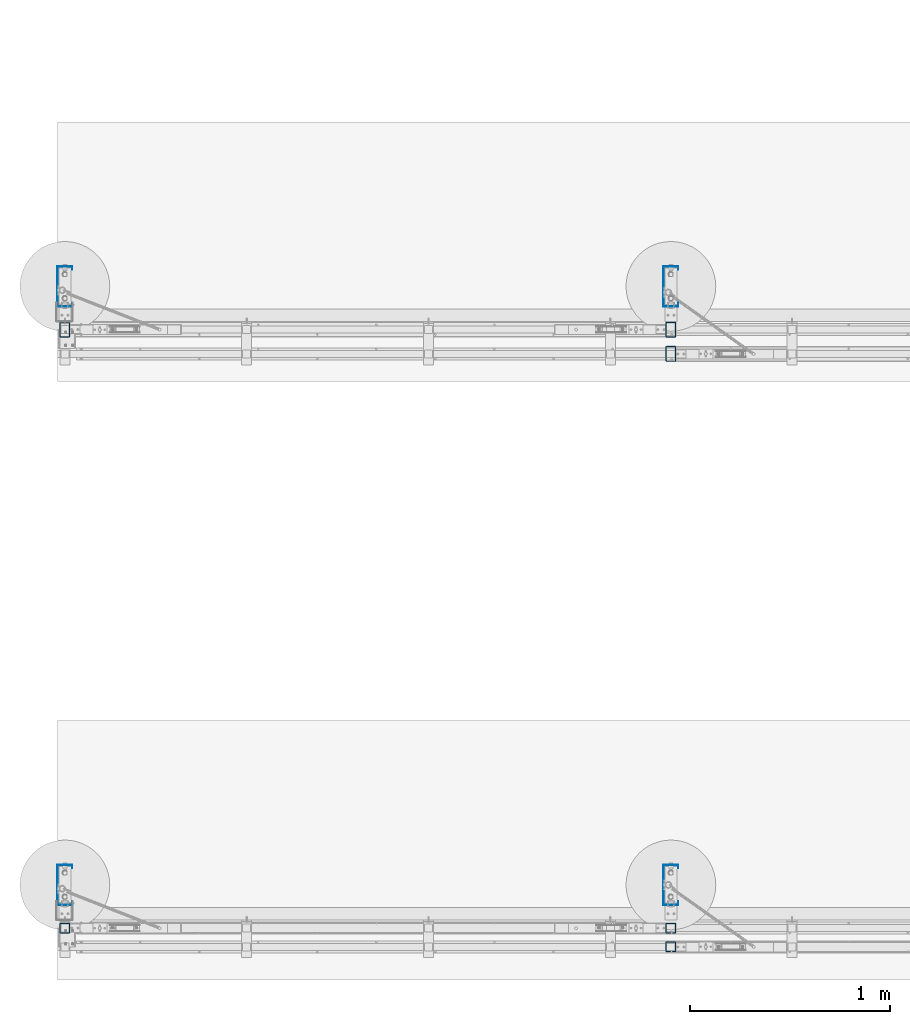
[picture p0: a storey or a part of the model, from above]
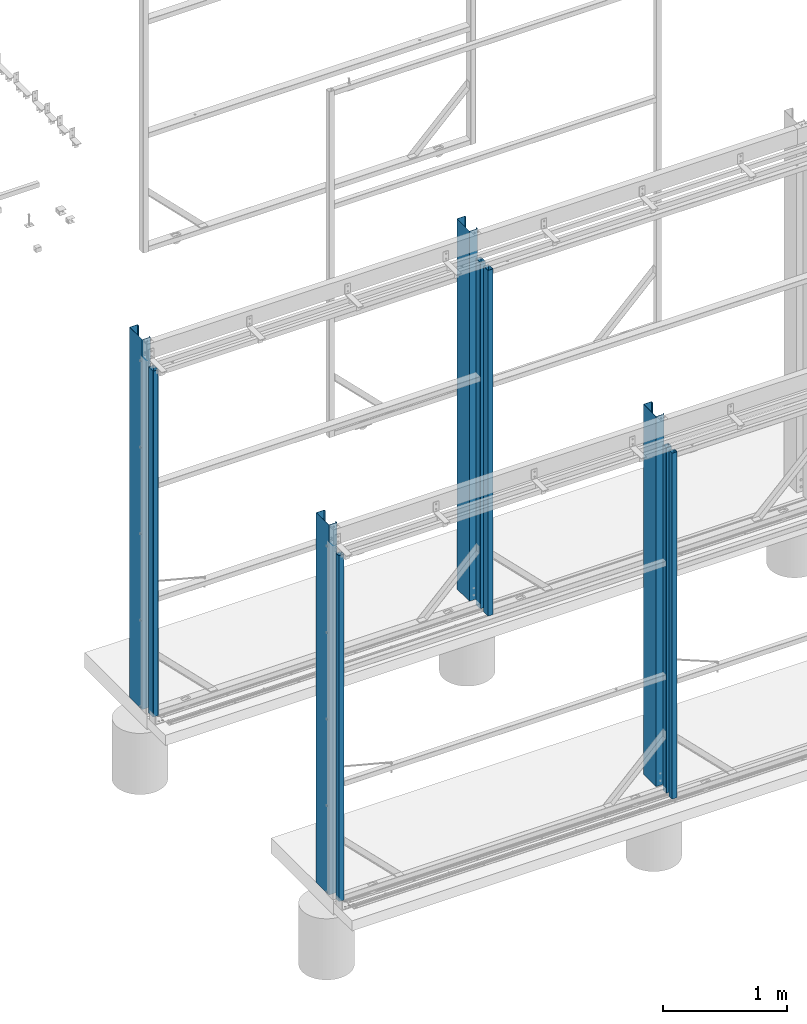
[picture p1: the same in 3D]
Properties of the parts of a building model (IFC2X3)

# File
Description: ViewDefinition[CoordinationView_V2.0, QuantityTakeOffAddOnView], Option [BaseQuantities:On], Option [GridExport:On], Option [Assemblies:On], Option [Bolts:On], Option [Rebars:On], Option [PourObjects:Off], Option [Welds:Off], Option [SurfaceTreatments:Off], Option [LocationBy:0], Option [ViewColors:Off], Option [SectionedSpine:Off], Option [PropertySets:On], Option [Export all:Off]
File name: Sliding Door.ifc
Time: 2026-09-21T11:43:24
Author: DESKTOP-BKNQL56\admin
Organization: Structural Designer
Written by: IFC Database Version: Work
Made in: Tekla Structures 2019 Service Pack 13, IFC Export Version: 4.0.0.0 Oct 18 2021

# IfcBuildingStorey, Undefined
In: Undefined
Elevation: 0 mm

# IfcBeam: C:150-19 (4)
In: Undefined
Description: C:150-19; Material: STEEL/G450
Tekla Common - Bottom elevation: +3.444; Top elevation: +3.596; Phase: 1; Class: 1
Tekla Quantity - Volume: 0 m3; Area per tons: 139.6 m2; Height: 152 mm; Width: 64 mm
Pset_BeamCommon - LoadBearing: no
Name | ASSEMBLY_POS = Reference | Weight (kg) | Gross footprint area (m2) | Net surface area (m2) | Tekla Quantity, Length (mm) = BaseQuantities, Length (mm) | OuterSurfaceArea (m2) | NetVolume (m3) | NetWeight (kg)
2 x FASCIA | Z/3676 | 13.9 | 0.2 | 1.9 | 3150.5 | 1.93746 | 0.00182811 | 14.3507
2 x FASCIA | Z/3652 | 26.6 | 0.3 | 3.7 | 6038 | 3.71212 | 0.00350361 | 27.5033

# IfcBeam: CC35-1.5-7-45 (5)
In: Undefined
Description: CC35-1.5-7-45
Tekla Common - Phase: 1; Class: 1
Tekla Quantity - Volume: 0 m3; Height: 35 mm; Width: 45 mm
Pset_BeamCommon - LoadBearing: no
Name | Material | ASSEMBLY_POS = Reference | Bottom elevation | Top elevation | Weight (kg) | Gross footprint area (m2) | Area per tons (m2) | Net surface area (m2) | Tekla Quantity, Length (mm) = BaseQuantities, Length (mm) | OuterSurfaceArea (m2) | NetVolume (m3) | NetWeight (kg)
TOP TRACK | STEEL/Steel_Undefined | TT/1 | +3.394 | +3.439 | 0.8 | 0 | 172.3 | 0.1 | 500 | 0.134899 | 0.00009975 | 0.783038
4 x TOP TRACK | STEEL/250 | Z/3674 | +3.397 | +3.442 | 14.4 | 0.3 | 171.8 | 2.5 | 9188.5 | 2.47211 | 0.00183311 | 14.3899

# IfcBeam: CC41-1.5-7-53, TOP TRACK BRACKET
In: Undefined
Description: CC41-1.5-7-53; Material: STEEL/Steel_Undefined
Default - ASSEMBLY_POS: SDB/9
Tekla Common - Bottom elevation: +3.388; Top elevation: +3.441; Phase: 1; Class: 1
Tekla Quantity - Weight: 0.1 kg; Volume: 0 m3; Gross footprint area: 0 m2; Area per tons: 177.9 m2; Net surface area: 0 m2; Height: 41 mm; Width: 53 mm; Length: 40 mm
Pset_BeamCommon - LoadBearing: no; Reference: SDB/9
BaseQuantities - Length: 40 mm; OuterSurfaceArea: 0.012985 m2; NetVolume: 0.0000093 m3; NetWeight: 0.073005 kg

# IfcBeam: CFCHS20*3 (4)
In: Undefined
Description: CFCHS20*3; Material: STEEL/250
Default - ASSEMBLY_POS: Z/3654
Tekla Common - Bottom elevation: -0.057; Top elevation: -0.044; Phase: 1; Class: 2
Tekla Quantity - Weight: 14.8 kg; Volume: 0 m3; Gross footprint area: 0 m2; Area per tons: 53.5 m2; Net surface area: 0.8 m2; Height: 60 mm; Width: 13 mm; Length: 8998.5 mm
Pset_BeamCommon - LoadBearing: no; Reference: Z/3654
BaseQuantities - Length: 8998.5 mm; OuterSurfaceArea: 0.794456 m2; NetVolume: 0.00189085 m3; NetWeight: 14.8432 kg

# IfcBeam: D12 (6)
In: Undefined
Description: D12; Material: STEEL/250
Default - ASSEMBLY_POS: Z/3662
Tekla Common - Bottom elevation: +1.062; Top elevation: +1.168; Phase: 1; Class: 5
Tekla Quantity - Weight: 0.5 kg; Volume: 0 m3; Gross footprint area: 0 m2; Area per tons: 46.4 m2; Net surface area: 0 m2; Height: 12 mm; Width: 12 mm; Length: 600 mm
Pset_BeamCommon - LoadBearing: no; Reference: Z/3662
BaseQuantities - Length: 600 mm; OuterSurfaceArea: 0.0222462 m2; NetVolume: 0.000061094 m3; NetWeight: 0.479588 kg

# IfcBeam: D450 (8)
In: Undefined
Description: D450; Material: Undefined/Undefined
Default - ASSEMBLY_POS: Z/3643
Tekla Common - Bottom elevation: -0.782; Top elevation: -0.182; Phase: 1; Class: 1
Tekla Quantity - Weight: 0 kg; Volume: 0.1 m3; Gross footprint area: 0.2 m2; Area per tons: 0 m2; Net surface area: 1.2 m2; Height: 450 mm; Width: 450 mm; Length: 600 mm
Pset_BeamCommon - LoadBearing: no; Reference: Z/3643
BaseQuantities - Length: 600 mm; OuterSurfaceArea: 1.16363 m2; NetVolume: 0.0949421 m3; NetWeight: 0 kg

# IfcBeam: D5 (12)
In: Undefined
Description: D5; Material: STEEL/250
Default - ASSEMBLY_POS: Z/3657
Tekla Common - Phase: 1; Class: 5
Tekla Quantity - Weight: 0 kg; Volume: 0 m3; Gross footprint area: 0 m2; Area per tons: 112.3 m2; Net surface area: 0 m2; Height: 5 mm; Width: 0 mm; Length: 71.6 mm
Pset_BeamCommon - LoadBearing: no; Reference: Z/3657
BaseQuantities - Length: 71.6493 mm; OuterSurfaceArea: 0.00139882 m2; NetVolume: 0.00000158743 m3; NetWeight: 0.0124613 kg
Name | Bottom elevation | Top elevation
6 x LINKS | +1.145 | +1.180
6 x LINKS | +1.160 | +1.165

# IfcBeam: EA50*50*3 (13)
In: Undefined
Description: EA50*50*3; Material: STEEL/300PLUS
Tekla Common - Bottom elevation: +0.033; Top elevation: +0.592; Phase: 1; Class: 11
Tekla Quantity - Weight: 1.8 kg; Volume: 0 m3; Gross footprint area: 0 m2; Area per tons: 86.4 m2; Net surface area: 0.2 m2; Height: 50 mm; Width: 50 mm; Length: 790 mm
Pset_BeamCommon - LoadBearing: no
BaseQuantities - Length: 790 mm; OuterSurfaceArea: 0.158 m2; NetVolume: 0.000227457 m3; NetWeight: 1.78554 kg
Name | ASSEMBLY_POS = Reference
ANGLE BRACE | AB/1
12 x Angle Brace | Z/3661

# IfcBeam: EA90*90*8 (5)
In: Undefined
Description: EA90*90*8; Material: STEEL/300PLUS
Tekla Common - Bottom elevation: -0.057; Top elevation: +0.033; Phase: 1; Class: 2
Tekla Quantity - Weight: 1 kg; Volume: 0 m3; Gross footprint area: 0 m2; Area per tons: 33 m2; Net surface area: 0 m2; Height: 90 mm; Width: 90 mm; Length: 95 mm
Pset_BeamCommon - LoadBearing: no
BaseQuantities - Length: 95 mm; OuterSurfaceArea: 0.03325 m2; NetVolume: 0.0001276 m3; NetWeight: 1.00166 kg
Name | ASSEMBLY_POS = Reference
DOOR STOPPER | DS/1
4 x DOOR STOPPER | Z/3640

# IfcBeam: FL6*50 (38)
In: Undefined
Description: FL6*50; Material: STEEL/250
Tekla Common - Phase: 1
Tekla Quantity - Volume: 0 m3; Gross footprint area: 0 m2; Net surface area: 0 m2; Height: 50 mm; Width: 6 mm
Pset_BeamCommon - LoadBearing: no
Name | ASSEMBLY_POS = Reference | Bottom elevation | Top elevation | Class | Weight (kg) | Area per tons (m2) | Tekla Quantity, Length (mm) | BaseQuantities, Length (mm) | OuterSurfaceArea (m2) | NetVolume (m3) | NetWeight (kg)
SLIDING DOOR BRACKET | PL/2518 | +3.441 | +3.541 | 10 | 0.8 | 48.3 | 357.1 | 357.137 | 0.0405756 | 0.00010695 | 0.839558
SLIDING DOOR BRACKET | PL/2517 | +3.441 | +3.541 | 10 | 0.8 | 48.4 | 328.1 | 328.137 | 0.0373276 | 0.00009825 | 0.771263
SLIDING DOOR BRACKET | PL/2516 | +3.441 | +3.541 | 10 | 0.8 | 48.4 | 327.1 | 327.137 | 0.0372156 | 0.00009795 | 0.768908
SLIDING DOOR BRACKET | PL/2515 | +3.441 | +3.541 | 10 | 0.8 | 48.4 | 308.1 | 308.137 | 0.0350876 | 0.00009225 | 0.724163
SLIDING DOOR BRACKET | PL/2514 | +3.441 | +3.541 | 10 | 0.6 | 48.7 | 238.1 | 238.137 | 0.0272476 | 0.00007125 | 0.559313
SLIDING DOOR BRACKET | PL/2513 | +3.441 | +3.541 | 10 | 0.5 | 48.8 | 218.1 | 218.137 | 0.0250076 | 0.00006525 | 0.512213
SLIDING DOOR BRACKET | PL/2512 | +3.441 | +3.541 | 10 | 0.5 | 48.9 | 209.1 | 209.137 | 0.0239996 | 0.00006255 | 0.491018
SLIDING DOOR BRACKET | PL/2511 | +3.441 | +3.541 | 10 | 0.5 | 48.9 | 199.1 | 199.137 | 0.0228796 | 0.00005955 | 0.467468
SLIDING DOOR BRACKET | PL/2114 | +3.441 | +3.541 | 9 | 0.6 | 48.4 | 307.1 | 307.137 | 0.0349756 | 0.00009195 | 0.721808
SLIDING DOOR BRACKET | PL/2107 | +3.441 | +3.541 | 9 | 0.6 | 48.6 | 277.1 | 277.137 | 0.0316156 | 0.00008295 | 0.651158
SLIDING DOOR BRACKET | PL/2090 | +3.441 | +3.541 | 9 | 0.6 | 48.6 | 258.1 | 258.137 | 0.0294876 | 0.00007725 | 0.606413
SLIDING DOOR BRACKET | PL/2089 | +3.441 | +3.541 | 9 | 0.6 | 48.4 | 278.1 | 278.137 | 0.0317276 | 0.00008325 | 0.653513
SLIDING DOOR BRACKET | PL/2071 | +3.441 | +3.541 | 9 | 0.5 | 48.9 | 213.1 | 213.137 | 0.0244476 | 0.00006375 | 0.500438
SLIDING DOOR BRACKET | PL/2070 | +3.441 | +3.541 | 9 | 0.5 | 48.9 | 193.1 | 193.137 | 0.0222076 | 0.00005775 | 0.453338
SLIDING DOOR BRACKET | PL/2049 | +3.441 | +3.541 | 9 | 0.5 | 49.1 | 184.1 | 184.137 | 0.0211996 | 0.00005505 | 0.432143
SLIDING DOOR BRACKET | PL/2048 | +3.441 | +3.541 | 9 | 0.5 | 49.1 | 174.1 | 174.137 | 0.0200796 | 0.00005205 | 0.408593
11 x DOOR BRACKET | Z/3659 | +3.444 | +3.544 | 10 | 0.6 | 48.4 | 308.1 | 308.137 | 0.0350876 | 0.00009225 | 0.724163
11 x DOOR BRACKET | Z/3647 | +3.444 | +3.544 | 9 | 0.6 | 48.4 | 278.1 | 278.137 | 0.0317276 | 0.00008325 | 0.653513

# IfcBeam: PLT1*263.6 (4)
In: Undefined
Description: PLT1*263.6; Material: STEEL/250
Default - ASSEMBLY_POS: Z/3641
Tekla Common - Bottom elevation: -0.032; Top elevation: +3.438; Phase: 1; Class: 1
Tekla Quantity - Weight: 7.2 kg; Volume: 0 m3; Gross footprint area: 0 m2; Area per tons: 256.3 m2; Net surface area: 1.8 m2; Height: 263.6 mm; Width: 1 mm; Length: 3470 mm
Pset_BeamCommon - LoadBearing: no; Reference: Z/3641
BaseQuantities - Length: 3470 mm; OuterSurfaceArea: 1.8464 m2; NetVolume: 0.000917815 m3; NetWeight: 7.20485 kg

# IfcBeam: PLT1.6*60 (8)
In: Undefined
Description: PLT1.6*60; Material: STEEL/250
Tekla Common - Bottom elevation: +3.441; Top elevation: +3.599; Phase: 1; Class: 1
Tekla Quantity - Weight: 0.2 kg; Volume: 0 m3; Gross footprint area: 0 m2; Area per tons: 164.6 m2; Net surface area: 0 m2; Height: 60 mm; Width: 1.6 mm; Length: 297.9 mm
Pset_BeamCommon - LoadBearing: no
BaseQuantities - Length: 297.881 mm; OuterSurfaceArea: 0.0371807 m2; NetVolume: 0.0000287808 m3; NetWeight: 0.225929 kg
Name | ASSEMBLY_POS = Reference
6 x FASCIA BRACKET | Z/52
2 x FASCIA BRACKET | Z/3655

# IfcBeam: PLT3*44, PLATE
In: Undefined
Description: PLT3*44; Material: STEEL/450
Tekla Quantity - Weight: 0.2 kg; Volume: 0 m3; Gross footprint area: 0 m2; Area per tons: 92.7 m2; Net surface area: 0 m2; Height: 44 mm; Width: 3 mm; Length: 156.8 mm
Tekla Common - Bottom elevation: +3.329; Top elevation: +3.373; Phase: 1; Class: 2
Default - ASSEMBLY_POS: PL/2519
Pset_BeamCommon - LoadBearing: no; Reference: PL/2519
BaseQuantities - Length: 156.85 mm; OuterSurfaceArea: 0.0154208 m2; NetVolume: 0.000021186 m3; NetWeight: 0.16631 kg

# IfcBeam: PLT3*65, PLATE
In: Undefined
Description: PLT3*65; Material: STEEL/450
Tekla Quantity - Weight: 0.2 kg; Volume: 0 m3; Gross footprint area: 0 m2; Area per tons: 90.9 m2; Net surface area: 0 m2; Height: 65 mm; Width: 3 mm; Length: 156.8 mm
Default - ASSEMBLY_POS: PL/2520
Tekla Common - Bottom elevation: +3.328; Top elevation: +3.372; Phase: 1; Class: 2
Pset_BeamCommon - LoadBearing: no; Reference: PL/2520
BaseQuantities - Length: 156.85 mm; OuterSurfaceArea: 0.0223212 m2; NetVolume: 0.0000312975 m3; NetWeight: 0.245685 kg

# IfcBeam: PLT6*61 (8)
In: Undefined
Description: PLT6*61; Material: STEEL/450
Default - ASSEMBLY_POS: Z/529
Tekla Common - Finish: GALVANIZE; Bottom elevation: -0.032; Top elevation: +0.123; Phase: 1; Class: 1
Tekla Quantity - Weight: 1.4 kg; Volume: 0 m3; Gross footprint area: 0 m2; Area per tons: 47.2 m2; Net surface area: 0.1 m2; Height: 61 mm; Width: 6 mm; Length: 481.9 mm
Pset_BeamCommon - LoadBearing: no; Reference: Z/529
BaseQuantities - Length: 481.908 mm; OuterSurfaceArea: 0.0665221 m2; NetVolume: 0.000179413 m3; NetWeight: 1.40839 kg

# IfcBeam: RHS:75x50x2.0 (13)
In: Undefined
Description: RHS:75x50x2.0
Tekla Quantity - Weight: 11.1 kg; Volume: 0 m3; Gross footprint area: 0.2 m2; Area per tons: 65.3 m2; Height: 75 mm; Width: 50 mm; Length: 2987.5 mm
Tekla Common - Phase: 1; Class: 14
Pset_BeamCommon - LoadBearing: no
BaseQuantities - Length: 2987.5 mm; OuterSurfaceArea: 0.725962 m2
Name | Material | Net surface area (m2) | ASSEMBLY_POS = Reference | Bottom elevation | Top elevation | NetVolume (m3) | NetWeight (kg)
Sliding Door Beam | STEEL/300PLUS | 0.8 | SDB/8 | +3.326 | +3.376 | 0.00144595 | 11.3507
3 x SLIDING DOOR | STEEL/300 | 0.6 | Z/3668 | +2.212 | +2.262 | 0.00144595 | 11.3507
SLIDING DOOR | STEEL/300 | 0.6 | Z/3678 | +1.097 | +1.147 | 0.00144595 | 11.3507
3 x SLIDING DOOR | STEEL/300 | 0.6 | Z/3666 | -0.017 | +0.033 | 0.00141859 | 11.1359
3 x SLIDING DOOR | STEEL/300 | 0.6 | Z/3669 | +3.326 | +3.376 | 0.00144595 | 11.3507
SLIDING DOOR | STEEL/300 | 0.6 | Z/3675 | +1.097 | +1.147 | 0.00144595 | 11.3507
SLIDING DOOR | STEEL/300 | 0.6 | Z/3667 | +1.097 | +1.147 | 0.00144595 | 11.3507

# IfcBeam: SHS:45X45X1.6, SLIDING DOOR INSERT
In: Undefined
Description: SHS:45X45X1.6; Material: STEEL/300PLUS
Default - ASSEMBLY_POS: Z/0(?)
Tekla Common - Bottom elevation: +3.329; Top elevation: +3.373; Phase: 1; Class: 1
Tekla Quantity - Weight: 0.1 kg; Volume: 0 m3; Gross footprint area: 0 m2; Area per tons: 82 m2; Net surface area: 0 m2; Height: 45 mm; Width: 45 mm; Length: 50 mm
Pset_BeamCommon - LoadBearing: no; Reference: Z/0(?)
BaseQuantities - Length: 50 mm; OuterSurfaceArea: 0.00975 m2; NetVolume: 0.000013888 m3; NetWeight: 0.109021 kg

# IfcBeam: SHS:50x50x2.0 (13)
In: Undefined
Description: SHS:50x50x2.0
Tekla Quantity - Weight: 8.8 kg; Volume: 0 m3; Gross footprint area: 0.1 m2; Area per tons: 65.7 m2; Net surface area: 0.6 m2; Height: 50 mm; Width: 50 mm; Length: 2987.5 mm
Tekla Common - Phase: 1; Class: 8
Pset_BeamCommon - LoadBearing: no
BaseQuantities - Length: 2987.5 mm; OuterSurfaceArea: 0.576588 m2
Name | Material | ASSEMBLY_POS = Reference | Bottom elevation | Top elevation | NetVolume (m3) | NetWeight (kg)
Sliding Door Beam | STEEL/300PLUS | SDB/4 | +3.326 | +3.376 | 0.0011472 | 9.00552
3 x SLIDING DOOR | STEEL/300 | Z/3665 | +2.212 | +2.262 | 0.0011472 | 9.00552
SLIDING DOOR | STEEL/300 | Z/3677 | +1.097 | +1.147 | 0.0011472 | 9.00552
3 x SLIDING DOOR | STEEL/300 | Z/3649 | -0.017 | +0.033 | 0.00111984 | 8.79074
3 x SLIDING DOOR | STEEL/300 | Z/3650 | +3.326 | +3.376 | 0.0011472 | 9.00552
SLIDING DOOR | STEEL/300 | Z/3673 | +1.097 | +1.147 | 0.0011472 | 9.00552
SLIDING DOOR | STEEL/300 | Z/3664 | +1.097 | +1.147 | 0.0011472 | 9.00552

# IfcColumn: C:200-19 (8)
In: Undefined
Description: C:200-19; Material: STEEL/G450
Default - ASSEMBLY_POS: Z/3644
Tekla Common - Bottom elevation: -0.032; Top elevation: +3.600; Phase: 1; Class: 1
Tekla Quantity - Weight: 20.3 kg; Volume: 0 m3; Gross footprint area: 0 m2; Area per tons: 138.5 m2; Net surface area: 2.8 m2; Height: 203 mm; Width: 76 mm; Length: 3632 mm
Pset_ColumnCommon - LoadBearing: no; Reference: Z/3644
BaseQuantities - Length: 3632 mm; OuterSurfaceArea: 2.81481 m2; NetVolume: 0.00265957 m3; NetWeight: 20.8776 kg

# IfcColumn: D12 (12)
In: Undefined
Description: D12; Material: STEEL/250
Tekla Common - Bottom elevation: +3.320; Top elevation: +3.430; Phase: 1; Class: 11
Tekla Quantity - Weight: 0.1 kg; Volume: 0 m3; Gross footprint area: 0 m2; Area per tons: 51.7 m2; Net surface area: 0 m2; Height: 12 mm; Width: 12 mm; Length: 110 mm
Pset_ColumnCommon - LoadBearing: no
BaseQuantities - Length: 110 mm; OuterSurfaceArea: 0.00438944 m2; NetVolume: 0.0000108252 m3; NetWeight: 0.0849779 kg
Name | ASSEMBLY_POS = Reference
6 x ROD | Z/3660
6 x ROD | Z/3645

# IfcColumn: D16 (16)
In: Undefined
Description: D16; Material: STEEL/300
Default - ASSEMBLY_POS: Z/65
Tekla Common - Bottom elevation: -0.151; Top elevation: -0.001; Phase: 1; Class: 1
Tekla Quantity - Weight: 0.2 kg; Volume: 0 m3; Gross footprint area: 0 m2; Area per tons: 36.2 m2; Net surface area: 0 m2; Height: 16 mm; Width: 16 mm; Length: 150 mm
Pset_ColumnCommon - LoadBearing: no; Reference: Z/65
BaseQuantities - Length: 150 mm; OuterSurfaceArea: 0.00770956 m2; NetVolume: 0.0000271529 m3; NetWeight: 0.21315 kg

# IfcColumn: RHS:75x50x2.0 (6)
In: Undefined
Description: RHS:75x50x2.0; Material: STEEL/300
Tekla Common - Bottom elevation: -0.017; Top elevation: +3.376; Phase: 1; Class: 14
Tekla Quantity - Weight: 12.6 kg; Volume: 0 m3; Gross footprint area: 0 m2; Area per tons: 65.3 m2; Net surface area: 0.8 m2; Height: 75 mm; Width: 50 mm; Length: 3393 mm
Default - ASSEMBLY_POS: Z/3658
Pset_ColumnCommon - LoadBearing: no; Reference: Z/3658
BaseQuantities - Length: 3393 mm; OuterSurfaceArea: 0.824499 m2; NetVolume: 0.00164221 m3; NetWeight: 12.8914 kg

# IfcColumn: SHS:50x50x2.0 (6)
In: Undefined
Description: SHS:50x50x2.0; Material: STEEL/300
Tekla Common - Bottom elevation: -0.017; Top elevation: +3.376; Phase: 1; Class: 8
Tekla Quantity - Weight: 10 kg; Volume: 0 m3; Gross footprint area: 0 m2; Area per tons: 65.7 m2; Net surface area: 0.6 m2; Height: 50 mm; Width: 50 mm; Length: 3393 mm
Pset_ColumnCommon - LoadBearing: no
BaseQuantities - Length: 3393 mm; OuterSurfaceArea: 0.654849 m2; NetVolume: 0.00130291 m3; NetWeight: 10.2279 kg
Name | ASSEMBLY_POS = Reference
4 x SLIDING DOOR | Z/3670
SLIDING DOOR | Z/3671
SLIDING DOOR | Z/3642

# IfcDiscreteAccessory: Angle Brace (4)
In: Undefined
Description: EA50*50*3; Material: STEEL/300PLUS
Tekla Common - Bottom elevation: +0.033; Top elevation: +0.592; Phase: 1; Class: 11
Tekla Quantity - Weight: 1.8 kg; Volume: 0 m3; Gross footprint area: 0 m2; Area per tons: 86.4 m2; Net surface area: 0.2 m2; Height: 50 mm; Width: 50 mm; Length: 790 mm
Pset_PlateCommon - LoadBearing: no; Reference: z/2810
BaseQuantities - NetArea: 0.158 m2; GrossArea: 0.158 m2; CrossSectionArea: 0.000295 m2; NetVolume: 0.000227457 m3; GrossVolume: 0.00023305 m3

# IfcDiscreteAccessory: DB-BU90 (4)
In: Undefined
Description: D88; Material: STEEL/250
Tekla Common - Bottom elevation: -0.054; Top elevation: +0.034; Phase: 1; Class: 5
Tekla Quantity - Weight: 1.2 kg; Volume: 0 m3; Gross footprint area: 0 m2; Area per tons: 16.1 m2; Net surface area: 0 m2; Height: 88 mm; Width: 88 mm; Length: 25 mm
Pset_PlateCommon - LoadBearing: no; Reference: z/2824
BaseQuantities - NetArea: 0.0187212 m2; GrossArea: 0.0187212 m2; CrossSectionArea: 0.005927 m2; NetVolume: 0.000148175 m3; GrossVolume: 0.000148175 m3

# IfcDiscreteAccessory: DOOR ROLLER (12)
In: Undefined
Description: D88; Material: STEEL/250
Tekla Common - Bottom elevation: -0.054; Top elevation: +0.034; Phase: 1; Class: 5
Tekla Quantity - Weight: 1.2 kg; Volume: 0 m3; Gross footprint area: 0 m2; Area per tons: 16.1 m2; Net surface area: 0 m2; Height: 88 mm; Width: 88 mm; Length: 25 mm
BaseQuantities - NetArea: 0.0187212 m2; GrossArea: 0.0187212 m2; CrossSectionArea: 0.005927 m2; NetVolume: 0.000148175 m3; GrossVolume: 0.000148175 m3
Pset_PlateCommon - LoadBearing: no; Reference: z/2791

# IfcDiscreteAccessory: LINK (2)
In: Undefined
Description: D5; Material: STEEL/250
Tekla Quantity - Weight: 0 kg; Volume: 0 m3; Gross footprint area: 0 m2; Area per tons: 112.3 m2; Net surface area: 0 m2; Height: 5 mm; Width: 0 mm; Length: 71.6 mm
Tekla Common - Phase: 1; Class: 5
Pset_PlateCommon - LoadBearing: no; Reference: z/2805
BaseQuantities - NetArea: 0.00139882 m2; GrossArea: 0.00163636 m2; CrossSectionArea: 0.0000176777 m2; NetVolume: 0.00000158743 m3; GrossVolume: 0.00000189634 m3
Name | Bottom elevation | Top elevation
LINK | -0.009 | -0.004
LINK | -0.019 | +0.007

# IfcDiscreteAccessory: PLATE (68)
In: Undefined
Tekla Common - Phase: 1
Tekla Quantity - Volume: 0 m3; Gross footprint area: 0 m2; Net surface area: 0 m2
Pset_PlateCommon - LoadBearing: no
Name | Description | Material | Bottom elevation | Top elevation | Class | Weight (kg) | Area per tons (m2) | Height (mm) | Width (mm) | Length (mm) | Reference | NetArea (m2) | GrossArea (m2) | CrossSectionArea (m2) | NetVolume (m3) | GrossVolume (m3)
2 x PLATE | PLT3*44 | STEEL/450 | -0.014 | +0.030 | 2 | 0.2 | 92.7 | 44 | 3 | 156.8 | z/2822 | 0.0154208 | 0.0154208 | 0.000132 | 0.000021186 | 0.000021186
2 x PLATE | PLT3*44 | STEEL/450 | +1.100 | +1.144 | 2 | 0.2 | 92.7 | 44 | 3 | 156.8 | z/2822 | 0.0154208 | 0.0154208 | 0.000132 | 0.000021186 | 0.000021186
2 x PLATE | PLT3*44 | STEEL/450 | +2.215 | +2.259 | 2 | 0.2 | 92.7 | 44 | 3 | 156.8 | z/2822 | 0.0154208 | 0.0154208 | 0.000132 | 0.000021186 | 0.000021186
2 x PLATE | PLT3*44 | STEEL/450 | +3.329 | +3.373 | 2 | 0.2 | 92.7 | 44 | 3 | 156.8 | z/2822 | 0.0154208 | 0.0154208 | 0.000132 | 0.000021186 | 0.000021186
2 x PLATE | PLT3*65 | STEEL/450 | -0.014 | +0.030 | 2 | 0.2 | 90.9 | 65 | 3 | 156.8 | z/2823 | 0.0223212 | 0.0223212 | 0.000195 | 0.0000312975 | 0.0000312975
2 x PLATE | PLT3*65 | STEEL/450 | +1.100 | +1.144 | 2 | 0.2 | 90.9 | 65 | 3 | 156.8 | z/2823 | 0.0223212 | 0.0223212 | 0.000195 | 0.0000312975 | 0.0000312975
2 x PLATE | PLT3*65 | STEEL/450 | +2.215 | +2.259 | 2 | 0.2 | 90.9 | 65 | 3 | 156.8 | z/2823 | 0.0223212 | 0.0223212 | 0.000195 | 0.0000312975 | 0.0000312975
2 x PLATE | PLT3*65 | STEEL/450 | +3.329 | +3.373 | 2 | 0.2 | 90.9 | 65 | 3 | 156.8 | z/2823 | 0.0223212 | 0.0223212 | 0.000195 | 0.0000312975 | 0.0000312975
32 x PLATE | PLT2*10 | STEEL/250 | -0.029 | -0.019 | 99 | 0 | 154.6 | 10 | 2 | 150 | z/2792 | 0.00364 | 0.0015 | 0.000004 | 0.000003 | 0.000003
4 x PLATE | PLT2*33 | STEEL/250 | -0.019 | -0.017 | 99 | 0 | 162.5 | 33 | 2 | 150 | z/2785 | 0.00574 | 0.00495 | 0.000004 | 0.0000045 | 0.0000099
8 x PLATE | PLT3*50 | STEEL/250 | +3.323 | +3.326 | 11 | 0.1 | 93.7 | 50 | 3 | 70 | p/1884 | 0.00772 | 0.0035 | 0.000009 | 0.0000105 | 0.0000105 | Tekla Common - Finish: GALVANIZE
8 x PLATE | PLT3*50 | STEEL/250 | +3.323 | +3.326 | 11 | 0.1 | 93.7 | 50 | 3 | 70 | z/2804 | 0.00772 | 0.0035 | 0.000009 | 0.0000105 | 0.0000105 | Tekla Common - Finish: GALVANIZE

# IfcDiscreteAccessory: ROD (6)
In: Undefined
Description: D12; Material: STEEL/250
Tekla Common - Phase: 1
Tekla Quantity - Volume: 0 m3; Gross footprint area: 0 m2; Net surface area: 0 m2; Height: 12 mm; Width: 12 mm
Pset_PlateCommon - LoadBearing: no
BaseQuantities - CrossSectionArea: 0.000101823 m2
Name | Bottom elevation | Top elevation | Class | Weight (kg) | Area per tons (m2) | Length (mm) | Reference | NetArea (m2) | GrossArea (m2) | NetVolume (m3) | GrossVolume (m3)
4 x ROD | +3.320 | +3.430 | 11 | 0.1 | 51.7 | 110 | z/2788 | 0.00438944 | 0.00424478 | 0.0000108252 | 0.0000112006
ROD | +3.320 | +3.430 | 11 | 0.1 | 51.7 | 110 | rd/2 | 0.00438944 | 0.00424478 | 0.0000108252 | 0.0000112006
ROD | -0.087 | -0.006 | 5 | 0.5 | 46.4 | 600 | rd/1 | 0.0222462 | 0.0222462 | 0.000061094 | 0.000061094

# IfcDiscreteAccessory: SLIDING DOOR (48)
In: Undefined
Description: SHS:45X45X1.6; Material: STEEL/300
Tekla Quantity - Weight: 0.1 kg; Volume: 0 m3; Gross footprint area: 0 m2; Area per tons: 82 m2; Net surface area: 0 m2; Height: 45 mm; Width: 45 mm; Length: 50 mm
Tekla Common - Phase: 1; Class: 11
Pset_PlateCommon - LoadBearing: no
BaseQuantities - NetArea: 0.00975 m2; GrossArea: 0.00975 m2; CrossSectionArea: 0.000303 m2; NetVolume: 0.000013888 m3; GrossVolume: 0.00001515 m3
Name | Bottom elevation | Top elevation | Reference
10 x SLIDING DOOR | +3.329 | +3.373 | z/2794
10 x SLIDING DOOR | +2.214 | +2.259 | z/2794
11 x SLIDING DOOR | +1.100 | +1.145 | z/2794
11 x SLIDING DOOR | -0.015 | +0.030 | z/2793
SLIDING DOOR | +3.329 | +3.373 | z/2800
SLIDING DOOR | +2.214 | +2.259 | z/2799
SLIDING DOOR | +1.100 | +1.145 | z/2798
SLIDING DOOR | -0.015 | +0.030 | z/2797
SLIDING DOOR | +3.329 | +3.373 | z/2796
SLIDING DOOR | +2.214 | +2.259 | z/2795

# IfcDiscreteAccessory: SLIDING DOOR BRACKET (44)
In: Undefined
Description: CC41-1.5-7-53; Material: STEEL/250
Tekla Quantity - Weight: 0.1 kg; Volume: 0 m3; Gross footprint area: 0 m2; Area per tons: 177.9 m2; Net surface area: 0 m2; Height: 41 mm; Width: 53 mm; Length: 40 mm
Tekla Common - Bottom elevation: +3.391; Top elevation: +3.444; Phase: 1; Class: 1
Pset_PlateCommon - LoadBearing: no; Reference: z/2790
BaseQuantities - NetArea: 0.012985 m2; GrossArea: 0.012985 m2; CrossSectionArea: 0.0002325 m2; NetVolume: 0.0000093 m3; GrossVolume: 0.0000093 m3

# IfcDiscreteAccessory: SPRING PIN (17)
In: Undefined
Description: D6; Material: STEEL/250
Tekla Common - Bottom elevation: +3.418; Top elevation: +3.424; Phase: 1; Class: 0
Tekla Quantity - Weight: 0 kg; Volume: 0 m3; Gross footprint area: 0 m2; Area per tons: 0 m2; Net surface area: 0 m2; Height: 6 mm; Width: 6 mm; Length: 30 mm
Pset_PlateCommon - LoadBearing: no
BaseQuantities - NetArea: 0.000601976 m2; GrossArea: 0.000601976 m2; CrossSectionArea: 0.0000254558 m2; NetVolume: 7.63675e-07 m3; GrossVolume: 7.63675e-07 m3
Name | Reference
16 x SPRING PIN | z/2801
SPRING PIN | sp/1

# IfcDiscreteAccessory: Sliding Door Beam (6)
In: Undefined
Material: STEEL/300PLUS
Tekla Common - Phase: 1
Tekla Quantity - Volume: 0 m3; Width: 50 mm; Length: 2987.5 mm
Pset_PlateCommon - LoadBearing: no
Name | Description | Bottom elevation | Top elevation | Class | Weight (kg) | Gross footprint area (m2) | Area per tons (m2) | Net surface area (m2) | Height (mm) | Reference | NetArea (m2) = GrossArea (m2) | CrossSectionArea (m2) | NetVolume (m3) | GrossVolume (m3)
Sliding Door Beam | RHS:75x50x2.0 | +2.212 | +2.262 | 14 | 11.1 | 0.2 | 65.3 | 0.8 | 75 | sdb/9 | 0.725962 | 0.000474 | 0.00144595 | 0.00141607
Sliding Door Beam | RHS:75x50x2.0 | +1.097 | +1.147 | 14 | 11.1 | 0.2 | 65.3 | 0.8 | 75 | sdb/8 | 0.725962 | 0.000474 | 0.00144595 | 0.00141607
Sliding Door Beam | RHS:75x50x2.0 | -0.017 | +0.033 | 14 | 11.1 | 0.2 | 65.3 | 0.8 | 75 | sdb/7 | 0.725962 | 0.000474 | 0.00141859 | 0.00141607
Sliding Door Beam | SHS:50x50x2.0 | +2.212 | +2.262 | 8 | 8.8 | 0.1 | 65.7 | 0.6 | 50 | sdb/5 | 0.576588 | 0.000374 | 0.0011472 | 0.00111732
Sliding Door Beam | SHS:50x50x2.0 | +1.097 | +1.147 | 8 | 8.8 | 0.1 | 65.7 | 0.6 | 50 | sdb/4 | 0.576588 | 0.000374 | 0.0011472 | 0.00111732
Sliding Door Beam | SHS:50x50x2.0 | -0.017 | +0.033 | 8 | 8.8 | 0.1 | 65.7 | 0.6 | 50 | sdb/3 | 0.576588 | 0.000374 | 0.00111984 | 0.00111732

# IfcDiscreteAccessory: Sliding Door Post (4)
In: Undefined
Material: STEEL/300
Tekla Common - Bottom elevation: -0.017; Top elevation: +3.376; Phase: 1
Tekla Quantity - Volume: 0 m3; Gross footprint area: 0 m2; Net surface area: 0.8 m2; Width: 50 mm; Length: 3393 mm
Pset_PlateCommon - LoadBearing: no
Name | Description | Class | Weight (kg) | Area per tons (m2) | Height (mm) | Reference | NetArea (m2) = GrossArea (m2) | CrossSectionArea (m2) | NetVolume (m3) | GrossVolume (m3)
2 x Sliding Door Post | RHS:75x50x2.0 | 14 | 12.6 | 65.3 | 75 | sdp/2 | 0.824499 | 0.000474 | 0.00164221 | 0.00160828
2 x Sliding Door Post | SHS:50x50x2.0 | 8 | 10 | 65.7 | 50 | sdp/1 | 0.654849 | 0.000374 | 0.00130291 | 0.00126898

# IfcDiscreteAccessory: TOP TRACK BRACKET (24)
In: Undefined
Description: CC38-1.5-7-50; Material: STEEL/Steel_Undefined
Tekla Common - Bottom elevation: +3.391; Top elevation: +3.441; Phase: 1; Class: 1
Tekla Quantity - Weight: 0.1 kg; Volume: 0 m3; Gross footprint area: 0 m2; Area per tons: 177.9 m2; Net surface area: 0 m2; Height: 38 mm; Width: 50 mm; Length: 40 mm
Pset_PlateCommon - LoadBearing: no; Reference: z/2821
BaseQuantities - NetArea: 0.012238 m2; GrossArea: 0.012238 m2; CrossSectionArea: 0.000219 m2; NetVolume: 0.00000876 m3; GrossVolume: 0.00000876 m3

# IfcElementAssembly (217)
In: Undefined
Name | PredefinedType | ASSEMBLY_POS = Assembly/Cast unit Mark | Assembly/Cast unit weight (kg) | Assembly/Cast unit bottom elevation | Assembly/Cast unit top elevation | Width (mm)
Sliding Door Beam | RIGID_FRAME | SDB/4 | 62.8 | -0.054 | +3.430 | 3484
Sliding Door Beam | RIGID_FRAME | SDB/8 | 78.2 | -0.054 | +3.430 | 3484
PLATE | RIGID_FRAME | PL/2519 | 0.2 | +3.329 | +3.373 | 44
PLATE | RIGID_FRAME | PL/2520 | 0.2 | +3.328 | +3.372 | 44
DOOR STOPPER | RIGID_FRAME | DS/1 | 1 | -0.057 | +0.033 | 90
TOP TRACK BRACKET | RIGID_FRAME | SDB/9 | 0.1 | +3.388 | +3.441 | 53
SLIDING DOOR INSERT | RIGID_FRAME | Z/0(?) | 0.1 | +3.329 | +3.373 | 45
PLATE | RIGID_FRAME | PL/2159 | 0.2 | +3.320 | +3.430 | 110
TOP TRACK | RIGID_FRAME | TT/1 | 0.8 | +3.394 | +3.439 | 45
ANGLE BRACE | RIGID_FRAME | AB/1 | 1.8 | +0.033 | +0.592 | 50
SLIDING DOOR BRACKET | RIGID_FRAME | PL/2518 | 1 | +3.391 | +3.541 | 267
SLIDING DOOR BRACKET | RIGID_FRAME | PL/2517 | 0.8 | +3.391 | +3.541 | 238
SLIDING DOOR BRACKET | RIGID_FRAME | PL/2516 | 0.8 | +3.391 | +3.541 | 237
SLIDING DOOR BRACKET | RIGID_FRAME | PL/2515 | 0.8 | +3.391 | +3.541 | 218
SLIDING DOOR BRACKET | RIGID_FRAME | PL/2514 | 0.6 | +3.391 | +3.541 | 148
SLIDING DOOR BRACKET | RIGID_FRAME | PL/2513 | 0.6 | +3.391 | +3.541 | 128
SLIDING DOOR BRACKET | RIGID_FRAME | PL/2512 | 0.6 | +3.391 | +3.541 | 119
SLIDING DOOR BRACKET | RIGID_FRAME | PL/2511 | 0.5 | +3.391 | +3.541 | 109
SLIDING DOOR BRACKET | RIGID_FRAME | PL/2114 | 0.8 | +3.391 | +3.541 | 217
SLIDING DOOR BRACKET | RIGID_FRAME | PL/2107 | 0.8 | +3.391 | +3.541 | 187
SLIDING DOOR BRACKET | RIGID_FRAME | PL/2090 | 0.6 | +3.391 | +3.541 | 168
SLIDING DOOR BRACKET | RIGID_FRAME | PL/2089 | 0.8 | +3.391 | +3.541 | 188
SLIDING DOOR BRACKET | RIGID_FRAME | PL/2071 | 0.6 | +3.391 | +3.541 | 123
SLIDING DOOR BRACKET | RIGID_FRAME | PL/2070 | 0.5 | +3.391 | +3.541 | 103
SLIDING DOOR BRACKET | RIGID_FRAME | PL/2049 | 0.5 | +3.391 | +3.541 | 94
SLIDING DOOR BRACKET | RIGID_FRAME | PL/2048 | 0.5 | +3.391 | +3.541 | 84
11 x DOOR BRACKET | RIGID_FRAME | Z/3659 | 0.8 | +3.391 | +3.544 | 218
6 x PLATE | RIGID_FRAME | Z/3651 | 0.2 | +1.112 | +1.212 | 6
SLIDING DOOR | RIGID_FRAME | Z/3678 | 11.1 | +1.097 | +1.147 | 50
SLIDING DOOR | RIGID_FRAME | Z/3675 | 11.1 | +1.097 | +1.147 | 50
SLIDING DOOR | RIGID_FRAME | Z/3667 | 11.1 | +1.097 | +1.147 | 50
4 x FOLDED CHANNEL | RIGID_FRAME | Z/3641 | 7.2 | -0.032 | +3.438 | 83
6 x ROD | RIGID_FRAME | Z/3660 | 0.2 | +3.320 | +3.430 | 50
12 x PLATE | RIGID_FRAME | Z/3648 | 1.2 | -0.054 | +0.034 | 88
6 x SLIDING DOOR | RIGID_FRAME | Z/3658 | 13.1 | -0.017 | +3.376 | 100
3 x SLIDING DOOR | RIGID_FRAME | Z/3669 | 11.1 | +3.326 | +3.376 | 50
4 x DOOR STOPPER | RIGID_FRAME | Z/3640 | 1 | -0.057 | +0.033 | 90
8 x BASEPLATE | RIGID_FRAME | Z/529 | 1.4 | -0.032 | +0.123 | 200.2
8 x COLUMN | RIGID_FRAME | Z/3644 | 20.3 | -0.032 | +3.600 | 76
4 x DOOR TRACK | RIGID_FRAME | Z/3654 | 14.8 | -0.057 | -0.044 | 13
6 x FASCIA BRACKET | RIGID_FRAME | Z/52 | 0.2 | +3.441 | +3.599 | 157.2
2 x FASCIA BRACKET | RIGID_FRAME | Z/3655 | 0.2 | +3.441 | +3.599 | 157.2
6 x LINKS | RIGID_FRAME | Z/3657 | 0 | +1.145 | +1.180 | 5
4 x ROD | RIGID_FRAME | Z/3662 | 0.5 | +1.062 | +1.168 | 12
6 x LINKS | RIGID_FRAME | Z/3657 | 0 | +1.160 | +1.165 | 5
2 x ROD | RIGID_FRAME | Z/3662 | 0.5 | +1.062 | +1.168 | 12.0001
12 x Angle Brace | RIGID_FRAME | Z/3661 | 1.8 | +0.033 | +0.592 | 50
3 x SLIDING DOOR | RIGID_FRAME | Z/3668 | 11.1 | +2.212 | +2.262 | 50
3 x SLIDING DOOR | RIGID_FRAME | Z/3666 | 11.1 | -0.017 | +0.033 | 50
4 x TOP TRACK | RIGID_FRAME | Z/3674 | 14.4 | +3.397 | +3.442 | 45
2 x SLAB | REINFORCEMENT_UNIT | Z/3656 | 3307.9 | -0.182 | -0.032 | 150 | Tekla Assembly - Cast unit type: Cast in place; Cast unit rebar weight: 0 kg
16 x THROUGH BOLTS | RIGID_FRAME | Z/65 | 0.2 | -0.151 | -0.001 | 16
8 x FOOTING |  | Z/3643 | 0 | -0.782 | -0.182 | 450
2 x SLAB | REINFORCEMENT_UNIT | Z/3653 | 661.6 | -0.157 | -0.057 | 100 | Tekla Assembly - Cast unit type: Cast in place; Cast unit rebar weight: 0 kg
2 x FASCIA | RIGID_FRAME | Z/3676 | 13.9 | +3.444 | +3.596 | 64
2 x FASCIA | RIGID_FRAME | Z/3652 | 26.6 | +3.444 | +3.596 | 64
11 x DOOR BRACKET | RIGID_FRAME | Z/3647 | 0.8 | +3.391 | +3.544 | 188
SLIDING DOOR | RIGID_FRAME | Z/3677 | 8.8 | +1.097 | +1.147 | 50
SLIDING DOOR | RIGID_FRAME | Z/3673 | 8.8 | +1.097 | +1.147 | 50
SLIDING DOOR | RIGID_FRAME | Z/3664 | 8.8 | +1.097 | +1.147 | 50
6 x ROD | RIGID_FRAME | Z/3645 | 0.2 | +3.320 | +3.430 | 50
4 x SLIDING DOOR | RIGID_FRAME | Z/3670 | 10.4 | -0.017 | +3.376 | 100
3 x SLIDING DOOR | RIGID_FRAME | Z/3650 | 8.8 | +3.326 | +3.376 | 50
3 x SLIDING DOOR | RIGID_FRAME | Z/3665 | 8.8 | +2.212 | +2.262 | 50
3 x SLIDING DOOR | RIGID_FRAME | Z/3649 | 8.8 | -0.017 | +0.033 | 50
PLATE | RIGID_FRAME | PL/2160 | 0.6 | -0.087 | +0.044 | 556.801
SLIDING DOOR | RIGID_FRAME | Z/3671 | 10.4 | -0.017 | +3.376 | 100
SLIDING DOOR | RIGID_FRAME | Z/3642 | 10.4 | -0.017 | +3.376 | 100

# IfcMechanicalFastener: Bolt assembly (477)
In: Undefined
Tekla Bolt - Location: Site
Name | NominalDiameter (mm) | NominalLength (mm) | Material = Bolt standard | Washer count | Washer diameter (mm) | Washer type | Washer name | Nut count | Nut type | Nut name | Slotted hole y (mm) | Slotted hole x (mm) | Bolt hole diameter (mm) | Bolt count | Bolt size (mm) | Bolt length (mm) | Bolt Name
68 x Bolt assembly | 6 | 25 | TEK_11TPIM | 2 | 6 | UNDEF_WASH | UNDEFINED_WASHER14G | 2 | UNDEF_NUT | UNDEFINED_NUTM6 | 0 | 0 | 6 | 2 | 6 | 25 | TEKSCREW_M6*25
20 x Bolt assembly | 6 | 8 | TEK_11TPIM | 0 | 6 | UNDEF_WASH | UNDEFINED_WASHER14G | 0 | UNDEF_NUT | UNDEFINED_NUTM6 | 0 | 0 | 6 | 2 | 6 | 8 | TEKSCREW_M6*25
5 x Bolt assembly | 6 | 7.8 | TEK_11TPIM | 0 | 6 | UNDEF_WASH | UNDEFINED_WASHER14G | 0 | UNDEF_NUT | UNDEFINED_NUTM6 | 0 | 0 | 6 | 4 | 6 | 7.8 | TEKSCREW_M6*25
38 x Bolt assembly | 6 | 25 | TEK_11TPIM | 4 | 6 | UNDEF_WASH | UNDEFINED_WASHER14G | 2 | UNDEF_NUT | UNDEFINED_NUTM6 | 0 | 0 | 6 | 2 | 6 | 25 | TEKSCREW_M6*25
34 x Bolt assembly | 6 | 3 | 8.8S | 0 | 6 | HARD | WASHERM6-HARD | 0 | 8.8-HEX | NUTM6-8.8-HEX | 0 | 0 | 6 | 1 | 6 | 3 | BOLTM6*5
17 x Bolt assembly | 12 | 3 | 8.8S | 0 | 12 | HARD | WASHERM12-HARD | 0 | 8.8-HEX | NUTM12-8.8-HEX | 0 | 0 | 14 | 1 | 14 | 3 | BOLTM12*16
12 x Bolt assembly | 12 | 49.9967 | 8.8S | 0 | 12 | HARD | WASHERM12-HARD | 0 | 8.8-HEX | NUTM12-8.8-HEX | 0 | 0 | 14 | 1 | 14 | 50 | BOLTM12*50
32 x Bolt assembly | 6 | 25 | TEK_11TPIM | 1 | 6 | UNDEF_WASH | UNDEFINED_WASHER14G | 1 | UNDEF_NUT | UNDEFINED_NUTM6 | 0 | 0 | 6 | 1 | 6 | 25 | TEKSCREW_M6*25
16 x Bolt assembly | 10 | 50 | 8.8S | 0 | 10 | HARD | WASHERM10-HARD | 0 | 8.8-HEX | NUTM10-8.8-HEX | 0 | 0 | 16 | 1 | 16 | 50 | BOLTM10*50
Bolt assembly | 6 | 6.6 | TEK_11TPIM | 0 | 6 | UNDEF_WASH | UNDEFINED_WASHER14G | 0 | UNDEF_NUT | UNDEFINED_NUTM6 | 0 | 0 | 6 | 2 | 6 | 6.6 | TEKSCREW_M6*25
16 x Bolt assembly | 6 | 16 | TEK_11TPIM | 0 | 6 | UNDEF_WASH | UNDEFINED_WASHER14G | 0 | UNDEF_NUT | UNDEFINED_NUTM6 | 0 | 0 | 6 | 2 | 6 | 16 | TEKSCREW_M6*25
28 x Bolt assembly | 6 | 6 | 8.8S | 0 | 6 | HARD | WASHERM6-HARD | 0 | 8.8-HEX | NUTM6-8.8-HEX | 0 | 0 | 6 | 1 | 6 | 6 | BOLTM6*10
8 x Bolt assembly | 5 | 25 | TEK_16TPIM | 10 | 5 | UNDEF_WASH | UNDEFINED_WASHER10G | 5 | UNDEF_NUT | UNDEFINED_NUTM5 | 0 | 0 | 7 | 5 | 5 | 25 | TEKSCREW_M5*25
12 x Bolt assembly | 5 | 25 | TEK_16TPIM | 18 | 5 | UNDEF_WASH | UNDEFINED_WASHER10G | 2 | UNDEF_NUT | UNDEFINED_NUTM5 | 0 | 0 | 7 | 2 | 5 | 25 | TEKSCREW_M5*25
8 x Bolt assembly | 20 | 16 | 8.8S | 0 | 20 | HARD | WASHERM20-HARD | 0 | 8.8-HEX | NUTM20-8.8-HEX | 0 | 0 | 20 | 2 | 20 | 16 | BOLTM20*25
16 x Bolt assembly | 12 | 30 | 8.8S | 2 | 12 | HARD | WASHERM12-HARD | 2 | 8.8-HEX | NUTM12-8.8-HEX | 4 | 8 | 14 | 2 | 12 | 30 | BOLTM12*30
120 x Bolt assembly | 6.16 | 25 | TEK_10TPII | 1 | 6.2 | UNDEF_WASH | UNDEFINED_WASHER14G | 1 | UNDEF_NUT | UNDEFINED_NUTM6 | 0 | 0 | 8.2 | 1 | 6.2 | 25 | TEKSCREW_14G*25
4 x Bolt assembly | 6.16 | 25 | TEK_10TPII | 2 | 6.2 | UNDEF_WASH | UNDEFINED_WASHER14G | 2 | UNDEF_NUT | UNDEFINED_NUTM6 | 0 | 0 | 8.2 | 2 | 6.2 | 25 | TEKSCREW_14G*25
16 x Bolt assembly | 5 | 25 | TEK_16TPIM | 4 | 5 | UNDEF_WASH | UNDEFINED_WASHER10G | 2 | UNDEF_NUT | UNDEFINED_NUTM5 | 0 | 0 | 7 | 2 | 5 | 25 | TEKSCREW_M5*25
6 x Bolt assembly | 5 | 25 | TEK_16TPIM | 8 | 5 | UNDEF_WASH | UNDEFINED_WASHER10G | 4 | UNDEF_NUT | UNDEFINED_NUTM5 | 0 | 0 | 7 | 4 | 5 | 25 | TEKSCREW_M5*25

# IfcPlate: FL6*50 (7)
In: Undefined
Description: FL6*50; Material: STEEL/250
Tekla Common - Phase: 1; Class: 5
Tekla Quantity - Weight: 0.2 kg; Volume: 0 m3; Gross footprint area: 0 m2; Area per tons: 50.1 m2; Net surface area: 0 m2; Height: 50 mm; Width: 6 mm; Length: 100 mm
Pset_PlateCommon - LoadBearing: no
BaseQuantities - Width: 50 mm; NetArea: 0.0118 m2; GrossArea: 0.005 m2; CrossSectionArea: 0.000036 m2; NetVolume: 0.00003 m3; GrossVolume: 0.00003 m3
Name | ASSEMBLY_POS = Reference | Bottom elevation | Top elevation
6 x PLATE | Z/3651 | +1.112 | +1.212
PLATE | PL/2160 | -0.056 | +0.044

# IfcPlate: PLT2*33 (12)
In: Undefined
Description: PLT2*33; Material: STEEL/250
Tekla Common - Bottom elevation: -0.019; Top elevation: -0.017; Phase: 1; Class: 99
Tekla Quantity - Weight: 0 kg; Volume: 0 m3; Gross footprint area: 0 m2; Area per tons: 162.5 m2; Net surface area: 0 m2; Height: 33 mm; Width: 2 mm; Length: 150 mm
Default - ASSEMBLY_POS: Z/3648
Pset_PlateCommon - LoadBearing: no; Reference: Z/3648
BaseQuantities - Width: 33 mm; NetArea: 0.00574 m2; GrossArea: 0.00495 m2; CrossSectionArea: 0.000004 m2; NetVolume: 0.0000045 m3; GrossVolume: 0.0000099 m3

# IfcPlate: PLT3*50, PLATE
In: Undefined
Description: PLT3*50; Material: STEEL/250
Tekla Common - Finish: GALVANIZE; Bottom elevation: +3.323; Top elevation: +3.326; Phase: 1; Class: 11
Tekla Quantity - Weight: 0.1 kg; Volume: 0 m3; Gross footprint area: 0 m2; Area per tons: 93.7 m2; Net surface area: 0 m2; Height: 50 mm; Width: 3 mm; Length: 70 mm
Default - ASSEMBLY_POS: PL/2159
Pset_PlateCommon - LoadBearing: no; Reference: PL/2159
BaseQuantities - Width: 50 mm; NetArea: 0.00772 m2; GrossArea: 0.0035 m2; CrossSectionArea: 0.000009 m2; NetVolume: 0.0000105 m3; GrossVolume: 0.0000105 m3

# IfcSlab: 100*300 (2)
In: Undefined
Description: 100*300; PredefinedType: FLOOR; Material: CONCRETE/N40
Tekla Common - Bottom elevation: -0.157; Top elevation: -0.057; Phase: 1; Class: 1
Tekla Quantity - Weight: 661.6 kg; Volume: 0.3 m3; Gross footprint area: 2.8 m2; Area per tons: 11.2 m2; Net surface area: 7.4 m2; Height: 300 mm; Width: 100 mm; Length: 9188.5 mm
Pset_SlabCommon - LoadBearing: no; Reference: Z/3653
BaseQuantities - Width: 100 mm; NetVolume: 0.275655 m3; NetArea: 2.75655 m2; NetWeight: 661.571 kg

# IfcSlab: 150*1000 (2)
In: Undefined
Description: 150*1000; PredefinedType: FLOOR; Material: CONCRETE/N40
Tekla Common - Bottom elevation: -0.182; Top elevation: -0.032; Phase: 1; Class: 1
Tekla Quantity - Weight: 3307.9 kg; Volume: 1.4 m3; Gross footprint area: 9.2 m2; Area per tons: 6.5 m2; Net surface area: 21.4 m2; Height: 1000 mm; Width: 150 mm; Length: 9188.5 mm
Pset_SlabCommon - LoadBearing: no; Reference: Z/3656
BaseQuantities - Width: 150 mm; NetVolume: 1.37828 m3; NetArea: 9.1885 m2; NetWeight: 3307.86 kg
